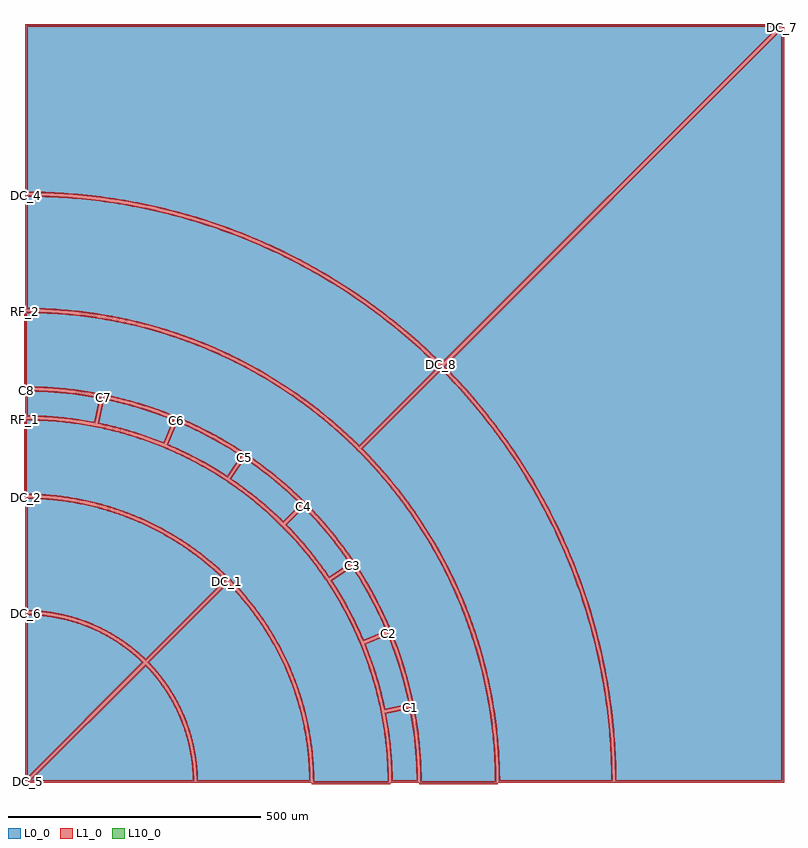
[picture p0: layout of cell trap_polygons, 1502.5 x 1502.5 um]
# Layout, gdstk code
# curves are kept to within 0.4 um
import gdstk
lib = gdstk.Library(unit=1e-6, precision=1e-09)
def P(c, l, *ps):  # polygons
    for p in ps: c.add(gdstk.Polygon(p, *l))
L0_0 = (0, 0)
L1_0 = (1, 0)
L10_0 = (10, 0)

trap_polygons = lib.new_cell('trap_polygons')
P(trap_polygons, L0_0, [(822.805,826.341),(782.779,864.352),(740.999,900.427),(712.217,923.36),(690.164,939.958),(644.909,971.565),(598.21,1000.996),(550.171,1028.183),(525.682,1040.916),(492.574,1056.986),(442.003,1079.111),(390.442,1098.819),(338.006,1116.064),(311.496,1123.752),(275.881,1133.021),(221.955,1144.807),(167.531,1154.028),(112.732,1160.663),(57.681,1164.698),(2.5,1166.122),(2.5,1497.5),(1493.964,1497.5)],
  [(1497.5,1493.964),(1497.5,2.5),(1166.122,2.5),(1164.698,57.681),(1160.663,112.732),(1154.028,167.531),(1144.807,221.955),(1133.021,275.881),(1123.752,311.496),(1116.064,338.006),(1098.819,390.442),(1079.111,442.003),(1056.986,492.574),(1040.916,525.682),(1028.183,550.171),(1000.996,598.21),(971.565,644.909),(939.958,690.164),(923.36,712.217),(900.427,740.999),(864.352,782.779),(826.341,822.805)],
  [(2.5,333.866),(33.622,332.178),(49.09,330.246),(66.998,327.084),(84.707,322.951),(99.689,318.645),(128.968,307.961),(157.123,294.593),(183.909,278.658),(209.092,260.294),(222.954,248.524),(234.311,237.846),(2.5,6.036)],
  [(6.036,2.5),(237.846,234.311),(248.524,222.954),(260.294,209.092),(278.658,183.909),(294.593,157.123),(307.961,128.968),(318.645,99.689),(322.951,84.707),(327.084,66.998),(330.246,49.09),(332.178,33.622),(333.866,2.5)],
  [(2.5,1161.122),(57.443,1159.703),(112.257,1155.686),(166.82,1149.079),(221.009,1139.898),(274.703,1128.162),(327.781,1113.899),(362.766,1103.002),(388.769,1094.107),(440.108,1074.484),(490.461,1052.454),(539.715,1028.066),(571.886,1010.524),(595.642,996.706),(642.14,967.403),(687.199,935.932),(730.719,902.364),(772.601,866.775),(799.567,841.965),(819.27,822.805),(660.17,663.706),(628.067,694.163),(594.56,723.069),(553.795,754.746),(517.508,780.074),(480.064,803.659),(441.548,825.448),(402.045,845.393),(361.644,863.449),(320.435,879.575),(271.459,895.902),(228.816,907.73),(185.662,917.529),(134.799,926.369),(90.87,931.704),(46.737,934.958),(2.5,936.122)],
  [(822.805,819.27),(841.965,799.567),(866.775,772.601),(902.364,730.719),(935.932,687.199),(967.403,642.14),(996.706,595.642),(1010.524,571.886),(1028.066,539.715),(1052.454,490.461),(1074.484,440.108),(1094.107,388.769),(1103.002,362.766),(1113.899,327.781),(1128.162,274.703),(1139.898,221.009),(1149.079,166.82),(1155.686,112.257),(1159.703,57.443),(1161.122,2.5),(936.122,2.5),(934.958,46.737),(931.704,90.87),(926.369,134.799),(917.529,185.662),(907.73,228.816),(895.902,271.459),(879.575,320.435),(863.449,361.644),(845.393,402.045),(825.448,441.548),(803.659,480.064),(780.074,517.508),(754.746,553.795),(723.069,594.56),(694.163,628.067),(663.706,660.17)],
  [(2.5,563.869),(29.025,563.128),(55.485,561.139),(86.196,557.248),(112.316,552.576),(138.188,546.68),(163.753,539.574),(188.956,531.273),(213.741,521.795),(238.052,511.162),(265.745,497.327),(288.848,484.275),(311.311,470.15),(336.643,452.357),(357.551,436.019),(377.668,418.715),(396.948,400.484),(237.847,241.382),(214.295,262.515),(201.804,272.234),(186.678,282.821),(159.484,299),(130.899,312.573),(101.173,323.42),(85.963,327.791),(67.983,331.986),(36.72,336.88),(18.318,338.38),(2.5,338.866)],
  [(400.484,396.948),(418.715,377.668),(436.019,357.551),(452.357,336.643),(470.15,311.311),(484.275,288.848),(497.327,265.745),(511.162,238.052),(521.795,213.741),(531.273,188.956),(539.574,163.753),(546.68,138.188),(552.576,112.316),(557.248,86.196),(561.139,55.485),(563.128,29.025),(563.869,2.5),(338.866,2.5),(338.38,18.318),(336.88,36.72),(331.986,67.983),(327.791,85.963),(323.42,101.173),(312.573,130.899),(299,159.484),(282.821,186.678),(272.234,201.804),(262.515,214.295),(241.382,237.847)],
  [(2.5,776.121),(39.331,775.128),(76.074,772.388),(112.645,767.907),(148.962,761.696),(138.768,710.449),(104.978,716.222),(70.952,720.389),(36.767,722.941),(2.5,723.871)],
  [(153.866,760.72),(189.795,752.561),(225.297,742.705),(260.291,731.176),(294.699,717.999),(274.704,669.726),(242.689,681.98),(210.13,692.705),(177.1,701.877),(143.672,709.474)],
  [(299.318,716.086),(332.966,701.073),(365.863,684.481),(397.935,666.346),(429.111,646.71),(400.082,603.265),(371.073,621.53),(341.232,638.401),(310.626,653.84),(279.323,667.813)],
  [(433.268,643.932),(463.341,622.644),(492.368,599.953),(520.287,575.909),(547.033,550.568),(510.086,513.622),(485.198,537.195),(459.221,559.563),(432.215,580.676),(404.24,600.488)],
  [(550.568,547.033),(575.909,520.287),(599.953,492.368),(622.644,463.341),(643.932,433.268),(600.488,404.24),(580.676,432.215),(559.563,459.221),(537.195,485.198),(513.622,510.086)],
  [(646.71,429.111),(666.346,397.935),(684.481,365.863),(701.073,332.966),(716.086,299.318),(667.813,279.323),(653.84,310.626),(638.401,341.232),(621.53,371.073),(603.265,400.082)],
  [(717.999,294.699),(731.176,260.291),(742.705,225.297),(752.561,189.795),(760.72,153.866),(709.474,143.672),(701.877,177.1),(692.705,210.13),(681.98,242.689),(669.726,274.704)],
  [(761.696,148.962),(767.907,112.645),(772.388,76.074),(775.128,39.331),(776.121,2.5),(723.871,2.5),(722.941,36.767),(720.389,70.952),(716.222,104.978),(710.449,138.768)],
  [(0,931.125),(43.862,930.091),(87.627,926.993),(131.197,921.836),(181.653,913.234),(224.471,903.663),(266.79,892.086),(315.407,876.078),(356.326,860.247),(396.454,842.507),(442.151,819.449),(480.261,797.711),(517.305,774.202),(553.201,748.974),(593.521,717.444),(626.659,688.689),(658.405,658.405),(688.689,626.659),(717.444,593.521),(748.974,553.201),(774.202,517.305),(797.711,480.261),(819.449,442.151),(842.507,396.454),(860.247,356.326),(876.078,315.407),(892.086,266.79),(903.663,224.471),(913.234,181.653),(921.836,131.197),(926.993,87.627),(930.091,43.862),(931.125,0),(781.125,0),(779.945,42.923),(777.057,79.616),(772.444,116.132),(766.116,152.39),(758.087,188.31),(748.375,223.811),(737.001,258.816),(721.665,298.924),(706.783,332.587),(690.331,365.512),(672.347,397.625),(649.482,433.97),(628.318,464.083),(601.867,497.908),(577.744,525.707),(552.339,552.339),(525.707,577.744),(497.908,601.867),(464.083,628.318),(433.97,649.482),(397.625,672.347),(365.512,690.331),(332.587,706.783),(298.924,721.665),(258.816,737.001),(223.811,748.375),(188.31,758.087),(152.39,766.116),(116.132,772.444),(79.616,777.057),(42.923,779.945),(0,781.125)],
  [(0,718.875),(33.864,718.077),(67.652,715.685),(106.877,710.886),(140.246,705.062),(173.303,697.673),(205.975,688.735),(243.51,676.376),(275.102,664.154),(306.082,650.458),(341.362,632.656),(370.786,615.873),(399.386,597.723),(427.099,578.246),(453.864,557.485),(479.621,535.486),(508.321,508.321),(535.486,479.621),(557.485,453.864),(578.246,427.099),(597.723,399.386),(615.873,370.786),(632.656,341.362),(650.458,306.082),(664.154,275.102),(676.376,243.51),(688.735,205.975),(697.673,173.303),(705.062,140.246),(710.886,106.877),(715.685,67.652),(718.077,33.864),(718.875,0),(568.875,0),(568.436,22.334),(566.753,49.086),(564.389,71.299),(561.155,93.402),(557.055,115.361),(552.097,137.142),(545.024,162.997),(538.204,184.269),(528.927,209.417),(520.297,230.021),(508.884,254.275),(498.509,274.058),(487.365,293.418),(475.47,312.325),(460.23,334.376),(446.747,352.187),(426.719,376.204),(405.402,399.084),(379.544,423.752),(355.685,443.967),(330.751,462.842),(301.037,482.696),(274.058,498.509),(246.25,512.815),(213.565,527.266),(184.269,538.204),(154.416,547.517),(124.096,555.175),(93.402,561.155),(62.425,565.44),(31.26,568.015),(0,568.875)])
P(trap_polygons, L1_0, [(457.992,1075.133),(425.831,1088.279),(399.955,1098.053),(347.544,1115.75),(294.355,1130.946),(240.506,1143.609),(186.119,1153.709),(158.761,1157.791),(122.148,1162.224),(67.012,1166.702),(39.38,1167.961),(5,1168.607),(5,1495),(457.992,1495),(457.992,1500),(0,1500),(0,1163.637),(57.557,1162.201),(112.491,1158.175),(167.172,1151.554),(221.479,1142.353),(248.454,1136.791),(284.202,1128.385),(337.281,1113.672),(363.545,1105.377),(398.244,1093.355),(432.546,1080.244),(457.992,1069.704)],
  [(822.805,826.341),(824.573,824.573),(1497.5,1497.5),(1496.464,1500),(457.992,1500),(457.992,1495),(1487.929,1495),(822.794,829.866),(784.457,866.205),(742.588,902.357),(699.054,936.487),(653.954,968.519),(607.389,998.38),(559.463,1026.005),(510.283,1051.331),(457.992,1075.133),(457.992,1069.704),(508.1,1046.832),(557.069,1021.615),(604.79,994.109),(635.858,974.53),(658.745,959.207),(696.063,932.48),(732.298,904.302),(753.496,886.717),(781.101,862.499),(821.048,824.562)],
  [(1500,451.469),(1495,451.469),(1495,5),(1168.607,5),(1167.961,39.38),(1166.702,67.012),(1164.007,103.793),(1161.224,131.314),(1157.791,158.761),(1152.205,195.215),(1141.676,249.522),(1133.234,285.423),(1123.663,321.04),(1112.973,356.337),(1104.227,382.579),(1091.605,417.232),(1077.896,451.469),(1072.466,451.469),(1093.355,398.244),(1110.976,346.057),(1118.855,319.666),(1128.385,284.202),(1140.57,230.485),(1147.275,194.38),(1151.554,167.172),(1158.175,112.491),(1162.201,57.557),(1163.637,0),(1500,0)],
  [(1500,1493.964),(1497.501,1493.964),(1495.732,1495.732),(822.816,822.816),(862.499,781.101),(898.496,739.41),(932.48,696.063),(964.375,651.156),(994.109,604.79),(1021.615,557.069),(1046.832,508.1),(1058.565,483.181),(1072.466,451.469),(1077.896,451.469),(1059.252,493.63),(1043.148,526.809),(1026.005,559.463),(1012.476,583.589),(993.557,615.247),(978.717,638.59),(947.401,684.19),(925.34,713.744),(908.188,735.445),(872.367,777.599),(853.719,798.028),(829.866,822.795),(1495,1487.929),(1495,451.469),(1500,451.469)],
  [(237.846,237.846),(222.668,252.125),(206.551,265.49),(189.633,277.827),(174.224,287.74),(155.985,298.022),(134.746,308.207),(121.723,308.207),(151.377,294.779),(164.971,287.392),(180.374,277.983),(195.242,267.75),(207.526,258.345),(230.755,237.826),(5,12.071),(5,308.207),(0,308.207),(0,3.536),(2.5,2.5)],
  [(132.344,309.246),(115.31,315.993),(97.934,321.803),(80.267,326.658),(62.363,330.544),(41.677,333.783),(18.216,335.881),(2.528,336.365),(2.5,333.866),(0,333.866),(0,308.207),(5,308.207),(5,331.337),(30.803,329.94),(56.36,326.547),(74.056,322.994),(89.051,319.185),(106.298,313.863),(121.723,308.207),(134.746,308.207)],
  [(237.868,230.712),(258.345,207.526),(267.75,195.242),(277.983,180.374),(287.392,164.971),(294.779,151.377),(307.61,123.229),(307.61,136.097),(298.022,155.985),(287.74,174.224),(277.827,189.633),(265.49,206.551),(252.125,222.668),(237.846,237.846),(4.268,4.268),(6.036,2.499),(6.036,0),(307.61,0),(307.61,5),(12.071,5)],
  [(336.394,0.029),(335.881,18.216),(334.391,36.477),(332.324,52.045),(328.998,70.062),(325.369,85.342),(320.24,102.93),(314.16,120.214),(307.61,136.097),(307.61,123.229),(313.863,106.298),(318.483,91.533),(322.408,76.568),(326.098,58.9),(329.691,33.37),(331.337,5),(307.61,5),(307.61,0)],
  [(265.221,900.374),(236.591,908.318),(200.632,916.932),(171.638,922.799),(135.159,928.843),(98.47,933.446),(69.006,936.085),(39.474,937.795),(5,938.605),(5,1158.607),(39.053,1157.967),(75.572,1156.158),(102.914,1154.045),(139.277,1150.223),(166.461,1146.605),(202.558,1140.781),(229.5,1135.668),(265.221,1127.861),(265.221,1132.992),(230.491,1140.569),(194.386,1147.274),(158.088,1152.836),(121.633,1157.25),(85.057,1160.512),(39.221,1162.964),(2.515,1163.622),(2.5,1161.122),(0,1161.122),(0,933.638),(31.913,933.079),(61.3,931.61),(90.627,929.216),(119.864,925.899),(156.239,920.459),(192.371,913.591),(228.205,905.305),(265.221,895.156)],
  [(518.89,1041.518),(491.517,1054.72),(457.991,1069.704),(432.546,1080.244),(398.245,1093.355),(363.547,1105.376),(328.487,1116.297),(293.099,1126.107),(265.221,1132.992),(265.221,1127.861),(300.677,1118.93),(335.834,1108.886),(379.306,1094.778),(413.662,1082.264),(464.413,1061.477),(518.89,1035.927)],
  [(518.89,782.157),(487.681,801.988),(455.715,820.574),(429.63,834.527),(396.428,850.801),(362.61,865.755),(335.148,876.751),(300.356,889.271),(265.221,900.374),(265.221,895.156),(298.756,884.534),(333.363,872.081),(360.678,861.143),(394.316,846.269),(427.342,830.081),(459.704,812.606),(491.353,793.869),(518.89,776.142)],
  [(822.805,822.805),(787.875,856.316),(753.489,886.723),(717.932,915.749),(681.257,943.351),(643.522,969.485),(604.786,994.111),(565.109,1017.19),(518.89,1041.518),(518.89,1035.927),(562.681,1012.819),(602.188,989.839),(640.757,965.32),(685.72,933.917),(714.847,911.815),(750.252,882.912),(784.489,852.636),(815.723,822.794),(660.159,667.23),(624.24,700.957),(590.417,729.675),(555.274,756.762),(518.89,782.157),(518.89,776.142),(558.23,748.355),(592.972,721.138),(626.389,692.309),(660.182,660.182)],
  [(1163.638,0.015),(1163.237,30.044),(1161.71,66.734),(1159.026,103.358),(1156.255,130.76),(1151.553,167.179),(1147.274,194.386),(1140.569,230.491),(1132.728,266.365),(1127.587,266.365),(1135.668,229.5),(1142.344,193.551),(1149.089,148.348),(1153.197,112.015),(1157.206,57.319),(1158.607,5),(938.605,5),(937.454,46.862),(934.881,83.749),(930.857,120.505),(925.389,157.075),(916.932,200.632),(904.477,250.875),(900.032,266.365),(894.814,266.365),(903.479,235.331),(912.047,199.564),(919.2,163.486),(923.895,134.439),(927.673,105.258),(931.098,68.639),(933.079,31.913),(933.638,0)],
  [(898.295,272.183),(884.428,314.331),(871.361,348.922),(856.942,382.971),(841.193,416.426),(816.957,462.166),(790.237,506.5),(779.916,522.24),(773.9,522.24),(789.973,497.593),(805.261,472.452),(819.749,446.842),(836.712,414.208),(852.377,380.931),(869.427,340.224),(882.153,305.716),(894.814,266.365),(900.032,266.365)],
  [(1130.591,275.294),(1121.342,310.832),(1110.975,346.06),(1096.463,389.606),(1083.623,424.01),(1062.344,474.813),(1039.842,522.24),(1034.252,522.24),(1050.188,489.405),(1061.477,464.413),(1075.602,430.688),(1088.657,396.534),(1100.627,361.985),(1108.886,335.834),(1118.93,300.677),(1127.587,266.365),(1132.728,266.365)],
  [(1038.685,524.553),(1017.19,565.109),(994.111,604.786),(969.485,643.522),(943.351,681.257),(915.749,717.932),(886.723,753.489),(856.316,787.875),(824.584,821.027),(822.805,819.27),(821.037,821.037),(660.182,660.182),(692.309,626.389),(721.138,592.972),(748.355,558.23),(773.9,522.24),(779.916,522.24),(752.363,561.219),(725,596.148),(696.017,629.744),(667.23,660.159),(822.795,815.724),(852.636,784.489),(876.966,757.194),(906.146,722.019),(928.478,693.067),(955.089,655.909),(985.057,609.978),(1012.819,562.681),(1034.252,522.24),(1039.842,522.24)],
  [(108.457,323.685),(84.024,330.873),(58.04,336.405),(31.704,339.9),(5,341.338),(5,561.349),(28.896,560.631),(55.239,558.651),(81.459,555.433),(108.457,550.795),(108.457,555.894),(82.185,560.38),(55.731,563.626),(29.153,565.624),(2.521,566.369),(2.5,563.869),(0,563.869),(0,336.394),(28.631,335.154),(54.608,331.913),(82.793,326.027),(108.457,318.408)],
  [(209.642,526.144),(185.603,535.1),(160.223,543.24),(134.489,550.176),(108.457,555.894),(108.457,550.795),(133.302,545.319),(158.809,538.444),(183.964,530.376),(209.642,520.757)],
  [(209.642,269.42),(185.832,286.362),(160.661,301.206),(134.312,313.843),(108.457,323.685),(108.457,318.408),(134.748,308.206),(160.613,295.553),(185.301,280.734),(209.642,263.052)],
  [(400.484,400.484),(379.342,420.571),(359.136,437.952),(334.561,457.001),(312.691,472.234),(290.128,486.422),(262.997,501.611),(235.073,515.288),(209.642,526.144),(209.642,520.757),(236.997,508.895),(264.567,495.122),(291.34,479.857),(317.235,463.146),(338.672,447.709),(355.966,434.085),(375.993,416.858),(393.398,400.469),(237.827,244.898),(224.004,257.603),(209.642,269.42),(209.642,263.052),(224.648,250.363),(237.866,237.866)],
  [(566.39,0.021),(565.624,29.153),(563.626,55.731),(560.38,82.185),(555.686,109.5),(550.588,109.5),(555.433,81.459),(558.651,55.239),(560.631,28.896),(561.348,5),(341.338,5),(340.722,21.106),(339.067,39.632),(336.847,55.419),(333.328,73.683),(328.821,91.727),(323.337,109.5),(318.051,109.5),(326.027,82.793),(331.913,54.608),(335.154,28.631),(336.394,0)],
  [(322.475,112.013),(315.895,129.41),(308.379,146.423),(301.206,160.661),(292.009,176.827),(280.438,194.657),(268.691,210.571),(262.312,210.571),(279.283,187.481),(294.294,162.909),(307.148,137.143),(318.051,109.5),(323.337,109.5)],
  [(555.026,112.814),(545.686,151.682),(533.628,189.794),(525.776,210.571),(520.381,210.571),(530.376,183.964),(538.444,158.809),(545.319,133.302),(550.588,109.5),(555.686,109.5)],
  [(524.108,214.689),(513.428,239.108),(501.611,262.997),(486.422,290.128),(472.234,312.691),(457.001,334.561),(437.952,359.136),(420.571,379.342),(402.266,398.701),(400.484,396.948),(398.716,398.716),(237.866,237.866),(250.363,224.648),(262.312,210.571),(268.691,210.571),(257.603,224.004),(244.898,237.827),(400.469,393.398),(416.858,375.993),(431.28,359.36),(447.709,338.672),(460.643,320.858),(477.557,295.095),(493.032,268.442),(507.021,240.981),(520.381,210.571),(525.776,210.571)],
  [(2.518,778.621),(2.482,773.621),(39.204,772.631),(75.829,769.9),(112.282,765.433),(146.019,759.714),(136.8,713.371),(105.34,718.696),(71.197,722.877),(36.894,725.437),(5,726.352),(5,776.121),(0,776.121),(0,721.389),(36.64,720.444),(70.707,717.901),(104.615,713.749),(140.736,707.528),(151.887,763.681),(113.007,770.381),(76.319,774.876),(39.458,777.625)],
  [(154.371,763.169),(153.36,758.272),(189.184,750.137),(224.571,740.313),(259.453,728.821),(291.426,716.629),(273.344,672.975),(243.527,684.336),(210.856,695.098),(177.711,704.301),(146.608,711.42),(156.318,760.233),(151.414,761.208),(140.736,707.528),(176.488,699.453),(209.404,690.313),(241.851,679.625),(276.064,666.477),(297.956,719.375),(261.13,733.531),(226.023,745.098),(190.407,754.985)],
  [(300.292,718.388),(298.345,713.783),(331.893,698.815),(364.684,682.276),(396.654,664.2),(425.633,646.005),(399.382,606.718),(372.355,623.677),(342.411,640.606),(311.699,656.098),(282.582,669.149),(301.628,715.129),(297.009,717.042),(276.064,666.477),(309.553,651.582),(340.054,636.196),(369.792,619.383),(400.782,599.813),(432.574,647.425),(399.217,668.493),(367.041,686.686),(334.038,703.332)],
  [(434.672,646.001),(431.865,641.863),(461.848,620.638),(490.782,598.02),(518.611,574.054),(543.484,550.555),(510.073,517.144),(486.874,539.05),(460.807,561.495),(433.708,582.682),(407.697,601.162),(435.347,642.543),(431.19,645.321),(400.782,599.813),(430.722,578.671),(457.635,557.63),(483.522,535.339),(510.099,510.099),(550.568,550.594),(521.963,577.764),(493.954,601.885),(464.833,624.65)],
  [(552.349,548.788),(548.788,545.278),(574.054,518.611),(598.02,490.782),(620.638,461.848),(640.45,433.948),(601.162,407.697),(582.682,433.708),(561.495,460.807),(539.05,486.874),(517.144,510.073),(552.336,545.265),(548.8,548.8),(510.099,510.099),(535.339,483.522),(557.63,457.635),(578.671,430.722),(599.813,400.782),(647.405,432.604),(624.65,464.833),(601.885,493.954),(577.764,521.963)],
  [(648.799,430.485),(644.621,427.737),(664.2,396.654),(682.276,364.684),(698.815,331.893),(712.803,300.664),(669.149,282.582),(656.098,311.699),(640.606,342.411),(623.677,372.355),(606.718,399.382),(648.099,427.032),(645.321,431.19),(599.813,400.782),(619.383,369.792),(636.196,340.054),(651.582,309.553),(666.477,276.064),(719.362,297.989),(703.332,334.038),(686.686,367.041),(668.493,399.217)],
  [(720.315,295.639),(715.682,293.759),(728.821,259.453),(740.313,224.571),(750.137,189.184),(757.763,155.826),(711.42,146.608),(704.301,177.711),(695.098,210.856),(684.336,243.527),(672.975,273.344),(718.956,292.389),(717.042,297.009),(666.477,276.064),(679.625,241.851),(690.313,209.404),(699.453,176.488),(707.528,140.736),(763.674,151.923),(754.985,190.407),(745.098,226.023),(733.531,261.13)],
  [(764.151,149.432),(759.24,148.492),(765.433,112.282),(769.9,75.829),(772.631,39.204),(773.603,5),(726.352,5),(725.437,36.894),(722.877,71.197),(718.696,105.34),(713.371,136.8),(762.183,146.51),(761.208,151.414),(707.528,140.736),(713.749,104.615),(717.901,70.707),(720.444,36.64),(721.389,0),(778.639,0.018),(777.625,39.458),(774.876,76.319),(770.381,113.007)],
  [(259.078,739.557),(224.528,750.77),(194.88,759.006),(164.931,766.072),(134.728,771.956),(104.317,776.651),(67.616,780.702),(36.914,782.755),(2.5,783.615),(2.5,928.615),(29.169,928.167),(58.309,926.793),(87.391,924.504),(116.388,921.302),(152.468,916.023),(188.313,909.331),(223.868,901.237),(259.078,891.753),(259.078,896.953),(225.074,906.089),(189.327,914.227),(160.517,919.723),(124.285,925.316),(87.862,929.482),(43.98,932.589),(0.01,933.625),(0,931.125),(-2.5,931.125),(-2.5,778.635),(24.457,778.241),(54.992,776.681),(85.442,773.923),(115.76,769.972),(151.902,763.664),(187.707,755.661),(223.095,745.979),(259.078,734.254)],
  [(497.582,789.971),(468.928,807.318),(443.338,821.649),(410.738,838.421),(384.2,850.909),(350.497,865.337),(323.144,875.919),(288.506,887.93),(259.078,896.953),(259.078,891.753),(293.888,880.894),(328.246,868.677),(362.097,855.12),(395.389,840.245),(421.587,827.411),(447.368,813.76),(472.709,799.307),(497.582,784.064)],
  [(497.582,605.368),(470.504,626.653),(440.463,648.121),(414.678,664.914),(382.896,683.71),(350.264,700.988),(322.473,714.198),(288.472,728.596),(259.078,739.557),(259.078,734.254),(292.308,721.674),(320.415,709.641),(348.029,696.515),(380.453,679.347),(412.032,660.671),(442.696,640.528),(472.378,618.964),(497.582,598.884)],
  [(682.314,637.252),(660.173,660.173),(639.11,680.583),(617.417,700.322),(595.115,719.37),(572.225,737.708),(548.771,755.319),(524.775,772.183),(497.582,789.971),(497.582,784.064),(527.981,763.925),(551.716,746.963),(580.616,724.727),(608.621,701.374),(646.242,666.87),(682.314,629.911)],
  [(682.314,385.365),(664.914,414.678),(644.642,445.539),(622.938,475.411),(599.852,504.228),(575.433,531.925),(549.738,558.441),(522.821,583.718),(497.582,605.368),(497.582,598.884),(524.024,575.895),(550.571,550.571),(571.762,528.531),(596.024,501.011),(618.964,472.378),(643.986,437.652),(663.887,406.83),(682.314,375.105)],
  [(780.331,512.581),(755.319,548.771),(733.192,578.002),(709.934,606.341),(682.314,637.252),(682.314,629.911),(710.847,597.529),(733.758,569.161),(759.754,533.964),(780.331,503.414)],
  [(780.331,71.714),(775.807,110.414),(768.568,152.878),(759.006,194.88),(747.151,236.293),(733.037,276.992),(719.175,311.215),(700.988,350.264),(682.314,385.365),(682.314,375.105),(696.515,348.029),(707.103,325.979),(719.356,297.967),(730.499,269.495),(744.204,228.947),(755.661,187.707),(765.956,139.888),(773.228,91.518),(777.449,42.786),(778.635,-2.5),(780.331,-2.5)],
  [(933.635,-2.49),(933.164,29.326),(931.294,65.939),(927.987,102.451),(924.311,131.549),(918.434,167.736),(912.712,196.502),(904.293,232.183),(894.481,267.506),(885.637,295.471),(873.354,330.013),(859.724,364.046),(844.769,397.518),(831.866,423.857),(814.584,456.189),(799.853,481.551),(780.331,512.581),(780.331,503.414),(799.307,472.709),(817.249,440.964),(833.931,408.539),(849.327,375.484),(860.702,348.62),(871.228,321.413),(883.175,286.961),(891.753,259.078),(899.451,230.94),(907.824,195.449),(913.515,166.837),(919.361,130.844),(923.789,94.65),(926.306,65.586),(927.909,36.458),(928.615,2.5),(783.615,2.5),(782.755,36.914),(780.331,71.714),(780.331,-2.5)],
  [(193.546,537.596),(172.291,544.78),(146.437,552.291),(120.258,558.576),(98.236,562.867),(71.612,566.87),(49.302,569.244),(26.915,570.741),(2.5,571.365),(2.5,716.365),(28.125,715.823),(50.595,714.586),(78.611,712.049),(100.938,709.228),(145.272,701.491),(167.234,696.581),(193.546,689.731),(193.546,694.92),(168.402,701.443),(140.733,707.514),(112.848,712.494),(84.789,716.375),(50.949,719.574),(22.659,721.019),(0.01,721.375),(0,718.875),(-2.5,718.875),(-2.5,566.385),(40.001,564.961),(62.151,562.955),(84.204,560.081),(114.854,554.607),(140.852,548.581),(166.537,541.337),(193.546,532.274)],
  [(371.202,618.536),(347.525,632.146),(327.497,642.75),(286.493,662.045),(265.556,670.718),(239.019,680.626),(193.546,694.92),(193.546,689.731),(237.362,675.909),(263.715,666.069),(284.507,657.456),(310.099,645.78),(330.231,635.721),(371.202,612.695)],
  [(371.202,434.37),(353.735,448.71),(332.205,464.876),(309.938,480.008),(286.982,494.076),(267.363,504.962),(243.28,516.996),(218.656,527.882),(193.546,537.596),(193.546,532.274),(220.845,521.544),(249.171,508.62),(276.743,494.16),(299.714,480.575),(318.35,468.438),(336.495,455.578),(354.122,442.016),(371.202,427.773)],
  [(507.046,513.109),(477.054,541.111),(442.136,569.998),(405.473,596.635),(371.202,618.536),(371.202,612.695),(407.303,589.319),(443.503,562.581),(477.953,533.623),(507.046,506.058)],
  [(507.046,263.389),(494.076,286.982),(480.008,309.938),(464.876,332.205),(448.71,353.735),(431.549,374.479),(413.43,394.392),(394.392,413.43),(371.202,434.37),(371.202,427.773),(394.148,406.729),(415.902,384.456),(433.551,364.437),(452.921,340.063),(468.438,318.35),(482.914,295.93),(496.318,272.853),(507.046,252.353)],
  [(583.605,424.014),(566.508,446.599),(548.538,468.496),(529.722,489.67),(507.046,513.109),(507.046,506.058),(529.853,482.129),(548.373,460.956),(566.047,439.071),(583.605,415.443)],
  [(583.605,2.5),(571.365,2.5),(570.248,35.877),(566.87,71.612),(562.078,102.654),(554.523,137.744),(544.78,172.291),(534.489,201.967),(522.584,231.032),(507.046,263.389),(507.046,252.353),(521.544,220.845),(534.382,187.661),(545.111,153.737),(552.735,123.551),(558.689,92.991),(562.955,62.151),(565.519,31.122),(566.385,-2.5),(583.605,-2.5)],
  [(721.385,-2.49),(720.819,28.321),(719.151,56.598),(716.375,84.789),(712.494,112.848),(707.514,140.733),(701.443,168.402),(694.291,195.81),(686.068,222.917),(676.788,249.68),(666.464,276.058),(655.112,302.011),(642.75,327.497),(629.397,352.479),(615.073,376.917),(599.801,400.774),(583.605,424.014),(583.605,415.443),(601.822,388.592),(616.614,364.665),(633.108,335.213),(645.78,310.099),(655.202,289.662),(666.069,263.715),(675.909,237.362),(683.031,216.014),(690.985,189.032),(697.873,161.758),(702.61,139.758),(707.555,112.066),(711.409,84.201),(714.167,56.206),(715.823,28.125),(716.365,2.5),(583.605,2.5),(583.605,-2.5)])
P(trap_polygons, L10_0, [(0,0),(0,0),(0,0),(0,0)])
trap_polygons.add(gdstk.Label('DC_8', (822.805,826.341), layer=2, texttype=0))
trap_polygons.add(gdstk.Label('DC_7', (1497.5,1493.964), layer=2, texttype=0))
trap_polygons.add(gdstk.Label('DC_6', (2.5,333.866), layer=2, texttype=0))
trap_polygons.add(gdstk.Label('DC_5', (6.036,2.5), layer=2, texttype=0))
trap_polygons.add(gdstk.Label('DC_4', (2.5,1161.122), layer=2, texttype=0))
trap_polygons.add(gdstk.Label('DC_3', (822.805,819.27), layer=2, texttype=0))
trap_polygons.add(gdstk.Label('DC_2', (2.5,563.869), layer=2, texttype=0))
trap_polygons.add(gdstk.Label('DC_1', (400.484,396.948), layer=2, texttype=0))
trap_polygons.add(gdstk.Label('C8', (2.5,776.121), layer=2, texttype=0))
trap_polygons.add(gdstk.Label('C7', (153.866,760.72), layer=2, texttype=0))
trap_polygons.add(gdstk.Label('C6', (299.318,716.086), layer=2, texttype=0))
trap_polygons.add(gdstk.Label('C5', (433.268,643.932), layer=2, texttype=0))
trap_polygons.add(gdstk.Label('C4', (550.568,547.033), layer=2, texttype=0))
trap_polygons.add(gdstk.Label('C3', (646.71,429.111), layer=2, texttype=0))
trap_polygons.add(gdstk.Label('C2', (717.999,294.699), layer=2, texttype=0))
trap_polygons.add(gdstk.Label('C1', (761.696,148.962), layer=2, texttype=0))
trap_polygons.add(gdstk.Label('RF_2', (0,931.125), layer=2, texttype=0))
trap_polygons.add(gdstk.Label('RF_1', (0,718.875), layer=2, texttype=0))

lib.write_gds('trap_polygons.gds')
